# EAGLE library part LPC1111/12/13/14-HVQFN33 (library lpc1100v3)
NXP Semiconductors LPC11xx microcontrollers ARM 32-bit Cortex-M0 Microcontroller with MPU CPU clock up to 50MHz Up to 32KByte on-chip Flash ROM with In-System Programming (ISP) and In-Application Programming (IAP) via On-Chip Bootloader Up to 8KByte SRAM Nested Vectored Interrupt Controller Up to 2 SPI controllers UART with full Modem Interface and RS485 Support Fast Mode I2C-Bus 4 Timers with 4 capture channels and 13 output channels Watchdog (WDT) Sytem tick timer 10-bit ADC with 8 channels Power Management Unit (PMU) Brownout detection 12MHz internal RC oscillator Serial Wire Debug/Trace port

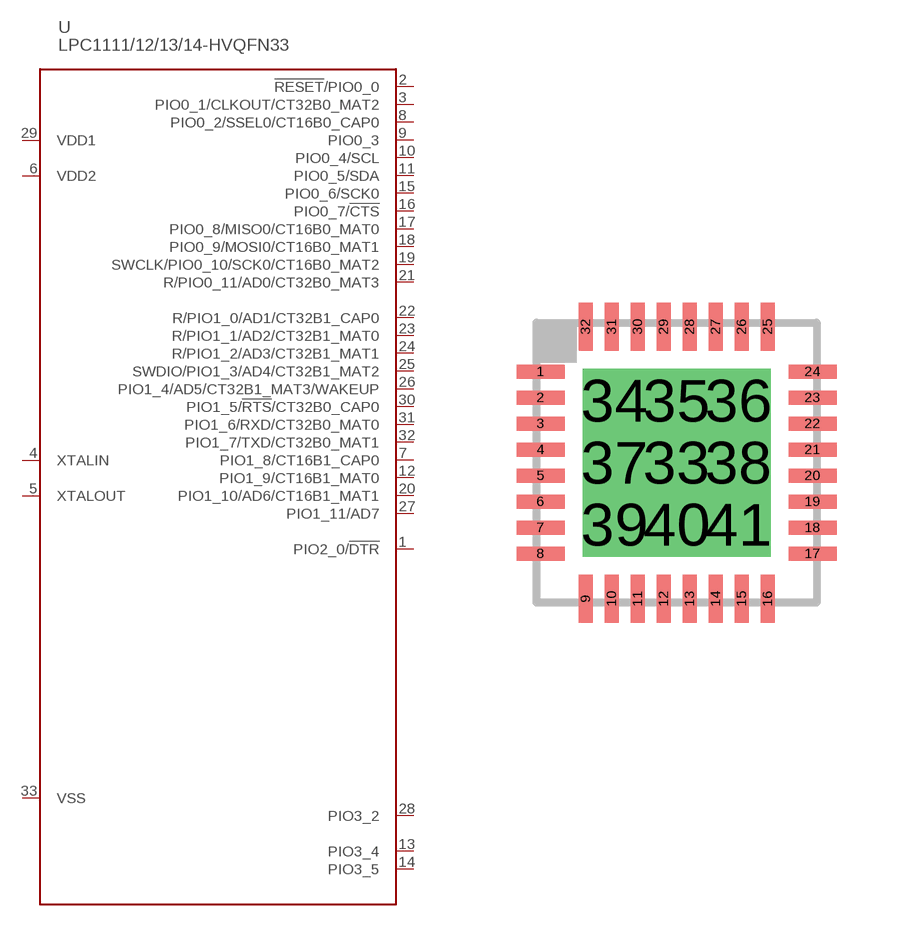
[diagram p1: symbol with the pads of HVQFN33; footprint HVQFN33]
Designator prefix -

## LPC1111/12/13/14-HVQFN33  [HVQFN33]
1  PIO2_0/!DTR!
2  !RESET!/PIO0_0
3  PIO0_1/CLKOUT/CT32B0_MAT2
4  XTALIN  pas
5  XTALOUT  pas
6  VDD2  pwr
7  PIO1_8/CT16B1_CAP0
8  PIO0_2/SSEL0/CT16B0_CAP0
9  PIO0_3
10  PIO0_4/SCL
11  PIO0_5/SDA
12  PIO1_9/CT16B1_MAT0
13  PIO3_4
14  PIO3_5
15  PIO0_6/SCK0
16  PIO0_7/!CTS!
17  PIO0_8/MISO0/CT16B0_MAT0
18  PIO0_9/MOSI0/CT16B0_MAT1
19  SWCLK/PIO0_10/SCK0/CT16B0_MAT2
20  PIO1_10/AD6/CT16B1_MAT1
21  R/PIO0_11/AD0/CT32B0_MAT3
22  R/PIO1_0/AD1/CT32B1_CAP0
23  R/PIO1_1/AD2/CT32B1_MAT0
24  R/PIO1_2/AD3/CT32B1_MAT1
25  SWDIO/PIO1_3/AD4/CT32B1_MAT2
26  PIO1_4/AD5/CT32B1_MAT3/WAKEUP
27  PIO1_11/AD7
28  PIO3_2
29  VDD1  pwr
30  PIO1_5/!RTS!/CT32B0_CAP0
31  PIO1_6/RXD/CT32B0_MAT0
32  PIO1_7/TXD/CT32B0_MAT1
33  VSS  pwr

## Footprint HVQFN33 (pad centres in mm)
HVQFN-33 7x7x0.85mm Plastic Thermal Enhanced Very Thin Quad Flat package
smd 1.2 x 0.35: 1 -3.4,2.275; 2 -3.4,1.625; 3 -3.4,0.975; 4 -3.4,0.325; 5 -3.4,-0.325; 6 -3.4,-0.975; 7 -3.4,-1.625; 8 -3.4,-2.275; 17 3.4,-2.275; 18 3.4,-1.625; 19 3.4,-0.975; 20 3.4,-0.325; 21 3.4,0.325; 22 3.4,0.975; 23 3.4,1.625; 24 3.4,2.275
smd 0.35 x 1.2: 9 -2.275,-3.4; 10 -1.625,-3.4; 11 -0.975,-3.4; 12 -0.325,-3.4; 13 0.325,-3.4; 14 0.975,-3.4; 15 1.625,-3.4; 16 2.275,-3.4; 25 2.275,3.4; 26 1.625,3.4; 27 0.975,3.4; 28 0.325,3.4; 29 -0.325,3.4; 30 -0.975,3.4; 31 -1.625,3.4; 32 -2.275,3.4
drill 0.5 pad 1.6 square: 33 0,0; 34 -1.55,1.55; 35 0,1.55; 36 1.55,1.55; 37 -1.55,0; 38 1.55,0; 39 -1.55,-1.55; 40 0,-1.55; 41 1.55,-1.55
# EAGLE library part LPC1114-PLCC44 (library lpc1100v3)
NXP Semiconductors LPC11xx microcontrollers ARM 32-bit Cortex-M0 Microcontroller with MPU CPU clock up to 50MHz Up to 32KByte on-chip Flash ROM with In-System Programming (ISP) and In-Application Programming (IAP) via On-Chip Bootloader Up to 8KByte SRAM Nested Vectored Interrupt Controller Up to 2 SPI controllers UART with full Modem Interface and RS485 Support Fast Mode I2C-Bus 4 Timers with 4 capture channels and 13 output channels Watchdog (WDT) Sytem tick timer 10-bit ADC with 8 channels Power Management Unit (PMU) Brownout detection 12MHz internal RC oscillator Serial Wire Debug/Trace port

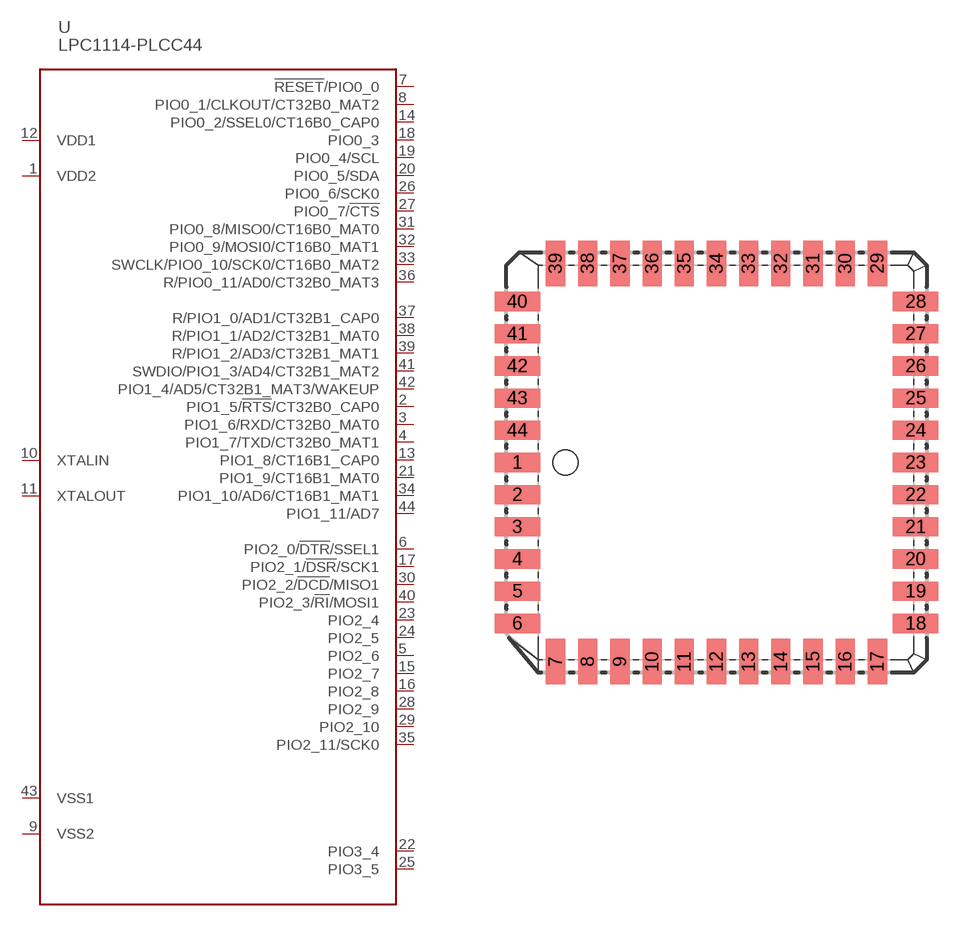
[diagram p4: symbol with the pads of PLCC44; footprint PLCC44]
Designator prefix -

## LPC1114-PLCC44  [PLCC44]
1  VDD2  pwr
2  PIO1_5/!RTS!/CT32B0_CAP0
3  PIO1_6/RXD/CT32B0_MAT0
4  PIO1_7/TXD/CT32B0_MAT1
5  PIO2_6
6  PIO2_0/!DTR!/SSEL1
7  !RESET!/PIO0_0
8  PIO0_1/CLKOUT/CT32B0_MAT2
9  VSS2  pwr
10  XTALIN  pas
11  XTALOUT  pas
12  VDD1  pwr
13  PIO1_8/CT16B1_CAP0
14  PIO0_2/SSEL0/CT16B0_CAP0
15  PIO2_7
16  PIO2_8
17  PIO2_1/!DSR!/SCK1
18  PIO0_3
19  PIO0_4/SCL
20  PIO0_5/SDA
21  PIO1_9/CT16B1_MAT0
22  PIO3_4
23  PIO2_4
24  PIO2_5
25  PIO3_5
26  PIO0_6/SCK0
27  PIO0_7/!CTS!
28  PIO2_9
29  PIO2_10
30  PIO2_2/!DCD!/MISO1
31  PIO0_8/MISO0/CT16B0_MAT0
32  PIO0_9/MOSI0/CT16B0_MAT1
33  SWCLK/PIO0_10/SCK0/CT16B0_MAT2
34  PIO1_10/AD6/CT16B1_MAT1
35  PIO2_11/SCK0
36  R/PIO0_11/AD0/CT32B0_MAT3
37  R/PIO1_0/AD1/CT32B1_CAP0
38  R/PIO1_1/AD2/CT32B1_MAT0
39  R/PIO1_2/AD3/CT32B1_MAT1
40  PIO2_3/!RI!/MOSI1
41  SWDIO/PIO1_3/AD4/CT32B1_MAT2
42  PIO1_4/AD5/CT32B1_MAT3/WAKEUP
43  VSS1  pwr
44  PIO1_11/AD7

## Footprint PLCC44 (pad centres in mm)
PLCC-44 (SOT187-2) Data Sheet Lead Plastic Leaded Chip Carrier
smd 1.8 x 0.76: 1 -7.86,0; 2 -7.86,-1.27; 3 -7.86,-2.54; 4 -7.86,-3.81; 5 -7.86,-5.08; 6 -7.86,-6.35; 18 7.86,-6.35; 19 7.86,-5.08; 20 7.86,-3.81; 21 7.86,-2.54; 22 7.86,-1.27; 23 7.86,0; 24 7.86,1.27; 25 7.86,2.54; 26 7.86,3.81; 27 7.86,5.08; 28 7.86,6.35; 40 -7.86,6.35; 41 -7.86,5.08; 42 -7.86,3.81; 43 -7.86,2.54; 44 -7.86,1.27
smd 0.76 x 1.8: 7 -6.35,-7.86; 8 -5.08,-7.86; 9 -3.81,-7.86; 10 -2.54,-7.86; 11 -1.27,-7.86; 12 0,-7.86; 13 1.27,-7.86; 14 2.54,-7.86; 15 3.81,-7.86; 16 5.08,-7.86; 17 6.35,-7.86; 29 6.35,7.86; 30 5.08,7.86; 31 3.81,7.86; 32 2.54,7.86; 33 1.27,7.86; 34 0,7.86; 35 -1.27,7.86; 36 -2.54,7.86; 37 -3.81,7.86; 38 -5.08,7.86; 39 -6.35,7.86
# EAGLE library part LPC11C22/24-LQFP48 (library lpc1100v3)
NXP Semiconductors LPC11Cxx microcontrollers ARM 32-bit Cortex-M0 Microcontroller with MPU CPU clock up to 50MHz 32KByte on-chip Flash ROM with In-System Programming (ISP) and In-Application Programming (IAP) via On-Chip Bootloader 8KByte SRAM Nested Vectored Interrupt Controller 2 SPI controllers CAN controller On-chip, high-speed CAN transciever UART with full Modem Interface and RS485 Support Fast Mode I2C-Bus 4 Timers with 4 capture channels and 12 output channels Watchdog (WDT) Sytem tick timer 10-bit ADC with 8 channels Power Management Unit (PMU) Brownout detection 12MHz internal RC oscillator Serial Wire Debug/Trace port

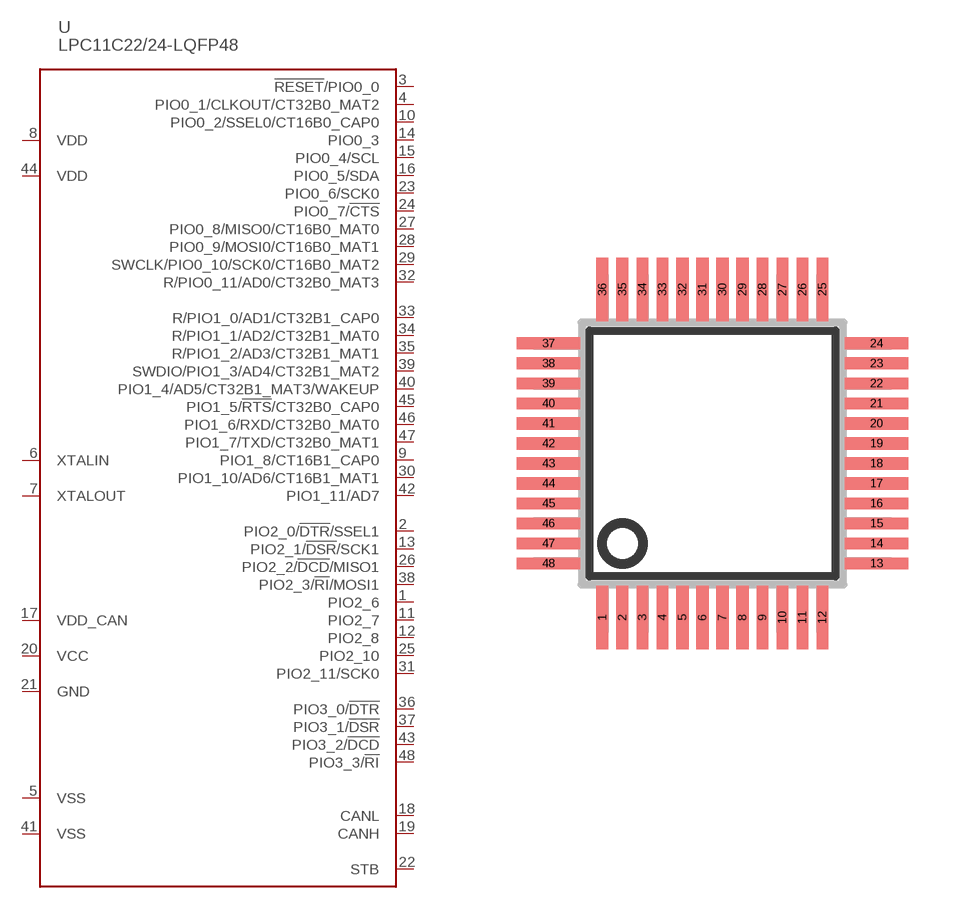
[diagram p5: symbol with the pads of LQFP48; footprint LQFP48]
Designator prefix -

## LPC11C22/24-LQFP48  [LQFP48]
1  PIO2_6
2  PIO2_0/!DTR!/SSEL1
3  !RESET!/PIO0_0
4  PIO0_1/CLKOUT/CT32B0_MAT2
5  VSS  pwr
6  XTALIN  pas
7  XTALOUT  pas
8  VDD  pwr
9  PIO1_8/CT16B1_CAP0
10  PIO0_2/SSEL0/CT16B0_CAP0
11  PIO2_7
12  PIO2_8
13  PIO2_1/!DSR!/SCK1
14  PIO0_3
15  PIO0_4/SCL
16  PIO0_5/SDA
17  VDD_CAN  pwr
18  CANL
19  CANH
20  VCC  pwr
21  GND  pwr
22  STB
23  PIO0_6/SCK0
24  PIO0_7/!CTS!
25  PIO2_10
26  PIO2_2/!DCD!/MISO1
27  PIO0_8/MISO0/CT16B0_MAT0
28  PIO0_9/MOSI0/CT16B0_MAT1
29  SWCLK/PIO0_10/SCK0/CT16B0_MAT2
30  PIO1_10/AD6/CT16B1_MAT1
31  PIO2_11/SCK0
32  R/PIO0_11/AD0/CT32B0_MAT3
33  R/PIO1_0/AD1/CT32B1_CAP0
34  R/PIO1_1/AD2/CT32B1_MAT0
35  R/PIO1_2/AD3/CT32B1_MAT1
36  PIO3_0/!DTR!
37  PIO3_1/!DSR!
38  PIO2_3/!RI!/MOSI1
39  SWDIO/PIO1_3/AD4/CT32B1_MAT2
40  PIO1_4/AD5/CT32B1_MAT3/WAKEUP
41  VSS  pwr
42  PIO1_11/AD7
43  PIO3_2/!DCD!
44  VDD  pwr
45  PIO1_5/!RTS!/CT32B0_CAP0
46  PIO1_6/RXD/CT32B0_MAT0
47  PIO1_7/TXD/CT32B0_MAT1
48  PIO3_3/!RI!

## Footprint LQFP48 (pad centres in mm)
LQFP-48 (SOT313-2) 7x7x1.4mm Data Sheet Plastic Low Profile Quad Flat Package
smd 0.3 x 1.6: 1 -2.75,-4.1; 2 -2.25,-4.1; 3 -1.75,-4.1; 4 -1.25,-4.1; 5 -0.75,-4.1; 6 -0.25,-4.1; 7 0.25,-4.1; 8 0.75,-4.1; 9 1.25,-4.1; 10 1.75,-4.1; 11 2.25,-4.1; 12 2.75,-4.1; 25 2.75,4.1; 26 2.25,4.1; 27 1.75,4.1; 28 1.25,4.1; 29 0.75,4.1; 30 0.25,4.1; 31 -0.25,4.1; 32 -0.75,4.1; 33 -1.25,4.1; 34 -1.75,4.1; 35 -2.25,4.1; 36 -2.75,4.1
smd 1.6 x 0.3: 13 4.1,-2.75; 14 4.1,-2.25; 15 4.1,-1.75; 16 4.1,-1.25; 17 4.1,-0.75; 18 4.1,-0.25; 19 4.1,0.25; 20 4.1,0.75; 21 4.1,1.25; 22 4.1,1.75; 23 4.1,2.25; 24 4.1,2.75; 37 -4.1,2.75; 38 -4.1,2.25; 39 -4.1,1.75; 40 -4.1,1.25; 41 -4.1,0.75; 42 -4.1,0.25; 43 -4.1,-0.25; 44 -4.1,-0.75; 45 -4.1,-1.25; 46 -4.1,-1.75; 47 -4.1,-2.25; 48 -4.1,-2.75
